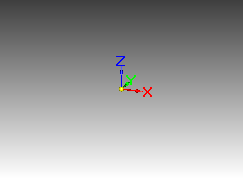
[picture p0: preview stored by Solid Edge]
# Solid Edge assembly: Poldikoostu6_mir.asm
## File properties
Author: Türk
Template: Iso Assembly.asm
Last saved by: Türk
Revision: 2
Application: Solid Edge
Username: Türk
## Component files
Polt110x20.par
Mutter.par
